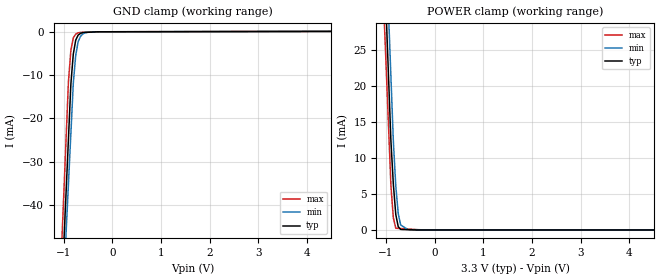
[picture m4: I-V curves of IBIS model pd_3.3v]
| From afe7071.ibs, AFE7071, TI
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[Model] pd_3.3v
Model_type Input
Vinl = 1.00000V
Vinh = 2.30000V
C_comp 542.000fF 490.000fF 594.000fF
| variable typ   min   max
[Voltage Range] 3.30000V 3.00000V 3.60000V
[POWER Clamp Reference] 3.30000V 3.00000V 3.60000V
[GND Clamp Reference] 0.00000V 0.00000V 0.00000V
[Temperature Range] 25   85   -40
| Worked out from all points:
|   GND clamp passes 1 mA (typ) near -0.71 V on its own axis
|   POWER clamp passes 1 mA (typ) near -0.77 V on its own axis
[GND Clamp]
-3.3V     -635.6mA   -594.3mA   -666.4mA
-900mV    -24.85mA   -35.21mA   -11.56mA
-850mV    -12.12mA   -23.56mA   -4.343mA
-800mV    -5.166mA   -11.91mA   -1.421mA
-750mV    -1.931mA   -5.437mA   -532.7uA
-700mV    -771.9uA   -2.269mA   -250.8uA
-650mV    -374.6uA   -1.047mA   -145.5uA
-600mV    -184.5uA   -476.1uA   -124.7uA
-500mV    -126.6uA   -113.9uA   -83.27uA
-250mV    -9.811uA   -10.13uA   -8.878uA
6.6V      109.1uA    119.5uA    156.9uA
[POWER Clamp]
-3.3V     450mA      451.7mA    409.4mA
-1.1V     48.81mA    57.14mA    39.75mA
-900mV    12.34mA    21.28mA    6.151mA
-850mV    6.331mA    12.31mA    1.665mA
-800mV    2.138mA    6.102mA    241.1uA
-750mV    463.4uA    2.283mA    219.2uA
-700mV    77.46uA    687.5uA    197.3uA
-550mV    44.26uA    61.72uA    131.5uA
-175mV    0A         0A         0A
6.6V      0A         0A         0A
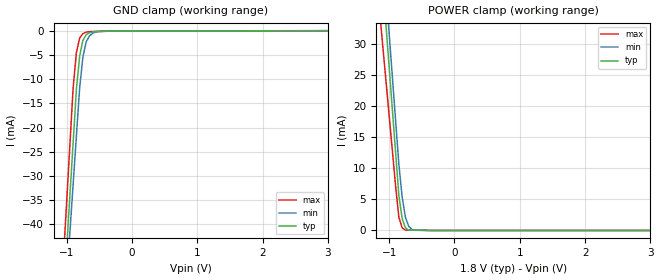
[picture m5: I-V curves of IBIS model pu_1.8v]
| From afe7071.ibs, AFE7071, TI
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[Model] pu_1.8v
Model_type Input
Vinl = 540.000mV
Vinh = 1.25000V
C_comp 562.000fF 550.000fF 574.000fF
| variable typ   min   max
[Voltage Range] 1.80000V 1.71000V 1.89000V
[POWER Clamp Reference] 1.80000V 1.71000V 1.89000V
[GND Clamp Reference] 0.00000V 0.00000V 0.00000V
[Temperature Range] 25   85   -40
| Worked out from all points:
|   GND clamp passes 1 mA (typ) near -0.71 V on its own axis
|   POWER clamp passes 1 mA (typ) near -0.77 V on its own axis
[GND Clamp]
-1.8V     -221.6mA   -211.4mA   -225.6mA
-900mV    -23.14mA   -31.74mA   -11.79mA
-850mV    -12.12mA   -21.76mA   -4.497mA
-800mV    -5.194mA   -11.78mA   -1.488mA
-750mV    -1.953mA   -5.371mA   -562.4uA
-700mV    -788.3uA   -2.247mA   -269.4uA
-650mV    -388.9uA   -1.041mA   -161.7uA
-600mV    -199.3uA   -481.2uA   -144.1uA
-500mV    -97.97uA   -129.3uA   -109uA
3.6V      49.78uA    63.83uA    37uA
[POWER Clamp]
-1.8V     137.2mA    144.9mA    110.2mA
-950mV    19.41mA    24.7mA     12.82mA
-900mV    12.47mA    17.63mA    7.092mA
-850mV    5.544mA    10.56mA    2.105mA
-800mV    1.926mA    5.358mA    405.2uA
-750mV    411.9uA    2.124mA    58.62uA
-700mV    59.34uA    668.9uA    51.56uA
-650mV    50.87uA    151.1uA    44.49uA
-600mV    42.39uA    65.71uA    37.43uA
3.6V      0A         0A         0A
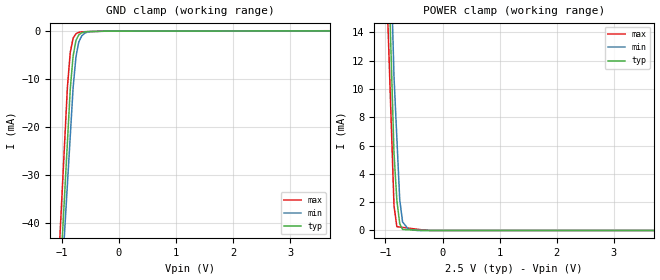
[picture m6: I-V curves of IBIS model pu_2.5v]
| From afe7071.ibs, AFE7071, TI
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[Model] pu_2.5v
Model_type Input
Vinl = 750.000mV
Vinh = 1.75000V
C_comp 562.000fF 550.000fF 574.000fF
| variable typ   min   max
[Voltage Range] 2.50000V 2.25000V 2.75000V
[POWER Clamp Reference] 2.50000V 2.25000V 2.75000V
[GND Clamp Reference] 0.00000V 0.00000V 0.00000V
[Temperature Range] 25   85   -40
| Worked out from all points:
|   GND clamp passes 1 mA (typ) near -0.71 V on its own axis
|   POWER clamp passes 1 mA (typ) near -0.77 V on its own axis
[GND Clamp]
-2.5V     -380mA     -355.4mA   -392.3mA
-900mV    -23.29mA   -32.02mA   -11.72mA
-850mV    -12.14mA   -21.91mA   -4.466mA
-800mV    -5.212mA   -11.81mA   -1.478mA
-750mV    -1.963mA   -5.391mA   -563uA
-700mV    -794.6uA   -2.258mA   -273.3uA
-650mV    -395uA     -1.05mA    -167.3uA
-600mV    -205.4uA   -487uA     -149.7uA
-500mV    -106.1uA   -135.2uA   -114.4uA
5V        64.59uA    60.83uA    92.3uA
[POWER Clamp]
-2.5V     230.4mA    251.3mA    219.8mA
-1.05V    32.71mA    40.01mA    25.86mA
-850mV    5.448mA    10.86mA    1.747mA
-800mV    2.13mA     6.526mA    267.4uA
-750mV    483.8uA    2.192mA    241.9uA
-700mV    70.55uA    605.6uA    216.5uA
-600mV    50.4uA     94.11uA    165.5uA
-450mV    20.16uA    0A         89.13uA
-200mV    0A         0A         0A
5V        0A         0A         0A
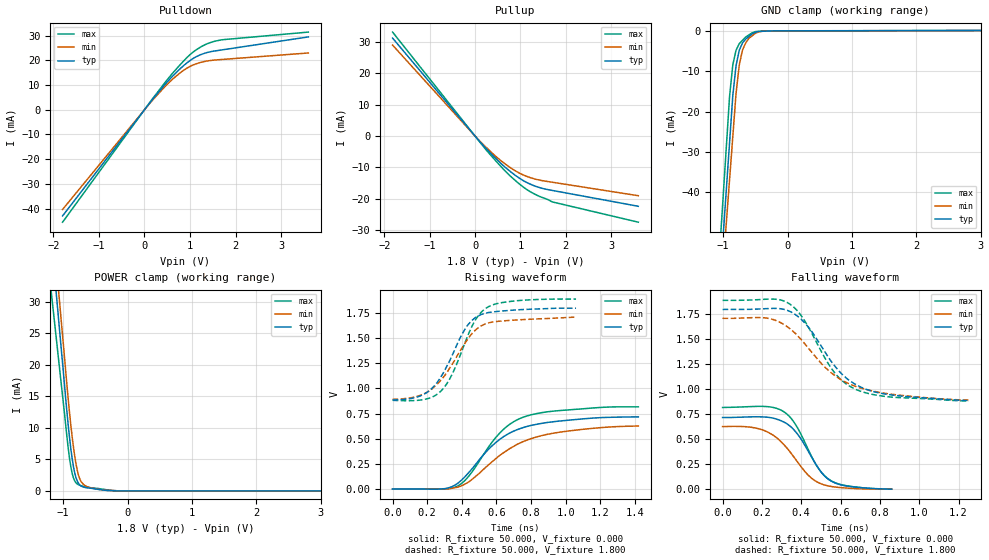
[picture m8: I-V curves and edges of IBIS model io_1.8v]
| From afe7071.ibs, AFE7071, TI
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[Model]   io_1.8v
Model_type I/O
Vinl=5.400E-01
Vinh=1.250E+00
Vref=0.000E+00
Rref=1.000E+06
Cref=1.500E-12
Vmeas=9.000E-01
C_comp   4.360E-13   4.000E-13   4.720E-13
[Voltage Range]   1.800E+00   1.710E+00   1.890E+00
[POWER Clamp Reference]   1.800E+00   1.710E+00   1.890E+00
[GND Clamp Reference]   0.000E+00   0.000E+00   0.000E+00
[Pullup Reference]   1.800E+00   1.710E+00   1.890E+00
[Pulldown Reference]   0.000E+00   0.000E+00   0.000E+00
[Temperature Range]   25   85   -40
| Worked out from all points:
|   slope of the pulldown table from 0 to 0.27 V, typ, clamps not added: 43.4 ohm
|   slope of the pullup table from 0 to 0.27 V, typ, clamps not added: 62 ohm
|   GND clamp passes 1 mA (typ) near -0.57 V on its own axis
|   POWER clamp passes 1 mA (typ) near -0.75 V on its own axis
|   rising waveform, R_fixture 50.000, V_fixture 0.000: 20-80 % time 268ps typ, 320ps min, 229ps max; typ from 0 V to 0.717 V
|   falling waveform, R_fixture 50.000, V_fixture 0.000: 20-80 % time 142ps typ, 161ps min, 136ps max; typ from 0.717 V to 0 V
|   rising waveform, R_fixture 50.000, V_fixture 1.800: 20-80 % time 167ps typ, 193ps min, 155ps max; typ from 0.886 V to 1.8 V
|   falling waveform, R_fixture 50.000, V_fixture 1.800: 20-80 % time 221ps typ, 266ps min, 193ps max; typ from 1.8 V to 0.886 V
[GND Clamp]
-1.8V     -236.1mA   -227.9mA   -240.1mA
-900mV    -27.61mA   -36.78mA   -16.16mA
-850mV    -16.02mA   -26.16mA   -8.42mA
-800mV    -8.649mA   -15.55mA   -4.816mA
-750mV    -4.824mA   -8.529mA   -3.182mA
-700mV    -3.016mA   -4.771mA   -2.357mA
-650mV    -2.052mA   -2.994mA   -1.533mA
-600mV    -1.403mA   -1.853mA   -1.009mA
-550mV    -754.4uA   -1.234mA   -485.4uA
-400mV    -116.2uA   -108.8uA   -124uA
-200mV    -9.259uA   -11.12uA   -12.43uA
3.6V      125.7uA    67.76uA    71.02uA
[Power Clamp]
-1.82V    111.8mA    116.9mA    89.74mA
-1.76V    105.1mA    110.7mA    85.43mA
-1.02V    21.47mA    25.85mA    16.06mA
-940mV    12.37mA    16.61mA    8.48mA
-880mV    6.628mA    10.36mA    3.792mA
-860mV    5.121mA    8.572mA    2.78mA
-820mV    2.838mA    5.499mA    1.581mA
-760mV    1.173mA    2.452mA    972.7uA
-720mV    768.7uA    1.456mA    825.9uA
-640mV    507.6uA    722.6uA    627.6uA
-320mV    72.94uA    86.73uA    178.8uA
3.6V      0A         0A         0A
[Pullup]
-1.82V    31.26mA    29.03mA    33.17mA
140mV     -2.332mA   -2.134mA   -2.556mA
580mV     -8.865mA   -7.98mA    -9.867mA
800mV     -11.56mA   -10.29mA   -13.05mA
1.06V     -14.17mA   -12.38mA   -16.21mA
1.34V     -16.04mA   -13.77mA   -18.7mA
1.7V      -17.32mA   -14.71mA   -20.98mA
3.6V      -22.38mA   -19.01mA   -27.46mA
[Pulldown]
-1.8V     -42.97mA   -40.36mA   -45.52mA
0V        0A         0A         0A
380mV     8.668mA    7.991mA    9.317mA
600mV     13.28mA    12.1mA     14.42mA
800mV     16.88mA    15.16mA    18.55mA
1.08V     20.87mA    18.2mA     23.5mA
1.22V     22.19mA    19.08mA    25.23mA
1.38V     23.18mA    19.73mA    26.73mA
1.7V      24.21mA    20.34mA    28.32mA
3.6V      29.47mA    22.97mA    31.42mA
[Rising Waveform]
R_fixture = 50.000
V_fixture = 0.000
V_fixture_min = 0.000
V_fixture_max = 0.000
|  time   V(typ)   V(min)   V(max)
0s        49.28uV    165.4uV    177.3uV
300ps     3.366mV    757.9uV    -189.1uV
380ps     60.88mV    20.15mV    33.2mV
440ps     163.2mV    70.27mV    126.8mV
540ps     368.8mV    218.2mV    381.2mV
620ps     494.6mV    335.4mV    557.8mV
680ps     559.5mV    404.8mV    647.4mV
760ps     613.8mV    475.9mV    717.2mV
1ns       681.5mV    573.4mV    784.7mV
1.42ns    716.9mV    625.9mV    817.1mV
[Falling Waveform]
R_fixture = 50.000
V_fixture = 0.000
V_fixture_min = 0.000
V_fixture_max = 0.000
|  time   V(typ)   V(min)   V(max)
0s        716.9mV    625.9mV    817.1mV
180ps     724.2mV    606.2mV    828.4mV
250ps     713.6mV    548.8mV    820.3mV
300ps     682.5mV    469.4mV    788.1mV
370ps     578mV      302.7mV    650.3mV
440ps     365.2mV    132.2mV    378.5mV
490ps     202.2mV    63.49mV    201.1mV
540ps     96.91mV    31.63mV    99.19mV
630ps     31.98mV    11.26mV    34.44mV
860ps     49.28uV    165.4uV    177.3uV
[Rising Waveform]
R_fixture = 50.000
V_fixture = 1.800
V_fixture_min = 1.710
V_fixture_max = 1.890
|  time   V(typ)   V(min)   V(max)
0s        886.1mV    892.4mV    882.2mV
170ps     933.4mV    938.6mV    886.9mV
220ps     989.1mV    985.4mV    908.5mV
280ps     1.117V     1.084V     975.2mV
340ps     1.312V     1.228V     1.128V
420ps     1.595V     1.453V     1.461V
490ps     1.717V     1.597V     1.711V
550ps     1.754V     1.65V      1.809V
620ps     1.768V     1.669V     1.85V
1.06ns    1.798V     1.709V     1.889V
[Falling Waveform]
R_fixture = 50.000
V_fixture = 1.800
V_fixture_min = 1.710
V_fixture_max = 1.890
|  time   V(typ)   V(min)   V(max)
0s        1.798V     1.709V     1.889V
220ps     1.806V     1.713V     1.9V
340ps     1.781V     1.609V     1.855V
390ps     1.717V     1.517V     1.762V
430ps     1.636V     1.426V     1.644V
570ps     1.234V     1.139V     1.165V
620ps     1.128V     1.077V     1.066V
680ps     1.044V     1.026V     996.6mV
850ps     945mV      952.3mV    923.2mV
1.25ns    886.1mV    892.4mV    882.2mV
[Ramp]
dV/dt_r   4.2300E-01/2.6740E-10   3.6800E-01/3.1990E-10   4.8100E-01/1.4870E-10
dV/dt_f   5.4800E-01/2.2130E-10   4.9100E-01/2.6560E-10   6.0400E-01/1.9290E-10
R_load = 50
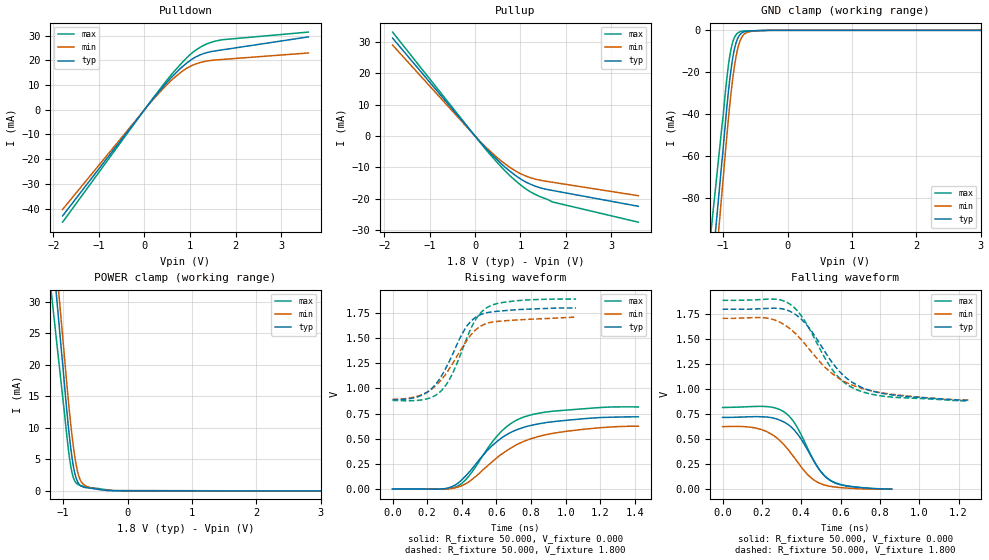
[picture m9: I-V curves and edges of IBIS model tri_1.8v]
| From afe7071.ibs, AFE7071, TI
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[Model]   tri_1.8v
Model_type 3-state
Vref=0.000E+00
Rref=1.000E+06
Cref=1.500E-12
Vmeas=9.000E-01
C_comp   4.840E-13   4.750E-13   4.930E-13
[Voltage Range]   1.800E+00   1.710E+00   1.890E+00
[POWER Clamp Reference]   1.800E+00   1.710E+00   1.890E+00
[GND Clamp Reference]   0.000E+00   0.000E+00   0.000E+00
[Pullup Reference]   1.800E+00   1.710E+00   1.890E+00
[Pulldown Reference]   0.000E+00   0.000E+00   0.000E+00
[Temperature Range]   25   85   -40
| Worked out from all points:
|   slope of the pulldown table from 0 to 0.27 V, typ, clamps not added: 43.4 ohm
|   slope of the pullup table from 0 to 0.27 V, typ, clamps not added: 62 ohm
|   GND clamp passes 1 mA (typ) near -0.70 V on its own axis
|   POWER clamp passes 1 mA (typ) near -0.75 V on its own axis
|   rising waveform, R_fixture 50.000, V_fixture 0.000: 20-80 % time 268ps typ, 320ps min, 229ps max; typ from 0 V to 0.717 V
|   falling waveform, R_fixture 50.000, V_fixture 0.000: 20-80 % time 142ps typ, 161ps min, 136ps max; typ from 0.717 V to 0 V
|   rising waveform, R_fixture 50.000, V_fixture 1.800: 20-80 % time 167ps typ, 194ps min, 155ps max; typ from 0.887 V to 1.8 V
|   falling waveform, R_fixture 50.000, V_fixture 1.800: 20-80 % time 221ps typ, 266ps min, 193ps max; typ from 1.8 V to 0.887 V
[GND Clamp]
-1.8V     -323.2mA   -353.4mA   -275.9mA
-1.02V    -62.73mA   -77.74mA   -45.99mA
-940mV    -35.81mA   -49.33mA   -22.1mA
-900mV    -24.11mA   -36.38mA   -12.79mA
-880mV    -19.15mA   -30.55mA   -9.297mA
-840mV    -11.2mA    -20.4mA    -4.552mA
-820mV    -8.255mA   -16.17mA   -3.113mA
-760mV    -2.989mA   -7.13mA    -981.1uA
-720mV    -1.466mA   -3.788mA   -499.9uA
-660mV    -617.7uA   -1.499mA   -294.2uA
-460mV    -147.3uA   -189.5uA   -131.9uA
3.6V      0A         0A         0A
[Power Clamp]
-1.8V     109.6mA    115.7mA    89.51mA
-1.76V    105.1mA    110.7mA    85.43mA
-1.02V    21.47mA    25.85mA    16.06mA
-940mV    12.37mA    16.61mA    8.48mA
-880mV    6.628mA    10.36mA    3.792mA
-860mV    5.121mA    8.572mA    2.78mA
-820mV    2.838mA    5.499mA    1.581mA
-760mV    1.173mA    2.452mA    972.7uA
-720mV    768.7uA    1.456mA    825.9uA
-640mV    507.6uA    722.6uA    627.6uA
-320mV    72.94uA    86.73uA    178.8uA
3.6V      0A         0A         0A
[Pullup]
-1.82V    31.26mA    29.03mA    33.17mA
140mV     -2.332mA   -2.134mA   -2.556mA
580mV     -8.865mA   -7.98mA    -9.867mA
800mV     -11.56mA   -10.29mA   -13.05mA
1.06V     -14.17mA   -12.38mA   -16.21mA
1.34V     -16.04mA   -13.77mA   -18.7mA
1.7V      -17.32mA   -14.71mA   -20.98mA
3.6V      -22.38mA   -19.01mA   -27.46mA
[Pulldown]
-1.8V     -42.97mA   -40.36mA   -45.52mA
0V        0A         0A         0A
380mV     8.668mA    7.991mA    9.317mA
600mV     13.28mA    12.1mA     14.42mA
800mV     16.88mA    15.16mA    18.55mA
1.08V     20.87mA    18.2mA     23.5mA
1.22V     22.19mA    19.08mA    25.23mA
1.38V     23.18mA    19.73mA    26.73mA
1.7V      24.21mA    20.34mA    28.32mA
3.6V      29.47mA    22.97mA    31.42mA
[Rising Waveform]
R_fixture = 50.000
V_fixture = 0.000
V_fixture_min = 0.000
V_fixture_max = 0.000
|  time   V(typ)   V(min)   V(max)
0s        -144.8uV   -503.5uV   -468uV
300ps     3.175mV    88.81uV    -834.4uV
380ps     60.75mV    19.47mV    32.55mV
440ps     163.1mV    69.57mV    126.2mV
540ps     369mV      217.4mV    380.6mV
620ps     494.9mV    334.6mV    557.2mV
680ps     559.9mV    404mV      646.7mV
760ps     614.2mV    475.1mV    716.5mV
1ns       682mV      572.6mV    784mV
1.42ns    717.5mV    625mV      816.4mV
[Falling Waveform]
R_fixture = 50.000
V_fixture = 0.000
V_fixture_min = 0.000
V_fixture_max = 0.000
|  time   V(typ)   V(min)   V(max)
0s        717.5mV    625mV      816.4mV
180ps     724.7mV    605.3mV    827.7mV
250ps     714.2mV    547.9mV    819.6mV
300ps     683mV      468.5mV    787.4mV
370ps     578.3mV    302mV      649.7mV
440ps     365.3mV    131.5mV    377.8mV
490ps     202.2mV    62.8mV     200.4mV
540ps     96.81mV    30.95mV    98.54mV
630ps     31.82mV    10.58mV    33.79mV
860ps     -144.8uV   -503.5uV   -468uV
[Rising Waveform]
R_fixture = 50.000
V_fixture = 1.800
V_fixture_min = 1.710
V_fixture_max = 1.890
|  time   V(typ)   V(min)   V(max)
0s        886.7mV    891.8mV    881.6mV
170ps     934mV      938.3mV    886.4mV
220ps     989.7mV    984.9mV    908mV
280ps     1.118V     1.084V     974.8mV
340ps     1.313V     1.227V     1.127V
420ps     1.596V     1.453V     1.461V
490ps     1.718V     1.596V     1.711V
540ps     1.752V     1.644V     1.798V
620ps     1.77V      1.669V     1.85V
1.06ns    1.8V       1.709V     1.889V
[Falling Waveform]
R_fixture = 50.000
V_fixture = 1.800
V_fixture_min = 1.710
V_fixture_max = 1.890
|  time   V(typ)   V(min)   V(max)
0s        1.8V       1.709V     1.889V
220ps     1.808V     1.713V     1.9V
340ps     1.782V     1.608V     1.854V
390ps     1.718V     1.517V     1.762V
430ps     1.638V     1.425V     1.643V
570ps     1.235V     1.138V     1.165V
620ps     1.129V     1.076V     1.066V
680ps     1.045V     1.025V     996.1mV
850ps     945.7mV    951.7mV    922.7mV
1.25ns    886.7mV    891.8mV    881.6mV
[Ramp]
dV/dt_r   4.2300E-01/2.6740E-10   3.6800E-01/3.1990E-10   4.8100E-01/1.4870E-10
dV/dt_f   5.4800E-01/2.2130E-10   4.9100E-01/2.6560E-10   6.0400E-01/1.9290E-10
R_load = 50
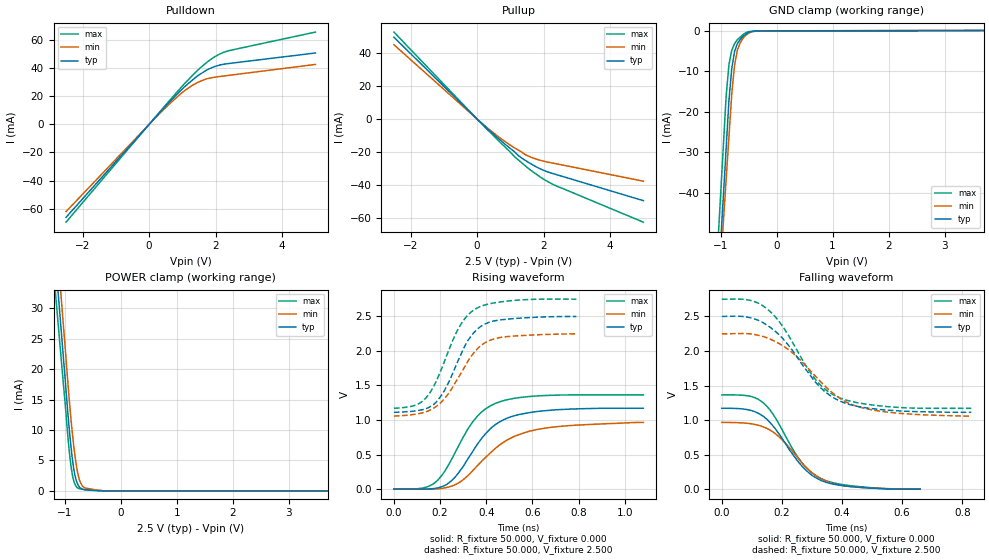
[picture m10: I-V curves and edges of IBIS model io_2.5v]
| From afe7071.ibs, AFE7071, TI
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[Model]   io_2.5v
Model_type I/O
Vinl=7.500E-01
Vinh=1.750E+00
Vref=0.000E+00
Rref=1.000E+06
Cref=0.000E+00
Vmeas=1.250E+00
C_comp   4.360E-13   4.000E-13   4.720E-13
[Voltage Range]   2.500E+00   2.250E+00   2.750E+00
[POWER Clamp Reference]   2.500E+00   2.250E+00   2.750E+00
[GND Clamp Reference]   0.000E+00   0.000E+00   0.000E+00
[Pullup Reference]   2.500E+00   2.250E+00   2.750E+00
[Pulldown Reference]   0.000E+00   0.000E+00   0.000E+00
[Temperature Range]   25   85   -40
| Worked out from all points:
|   slope of the pulldown table from 0 to 0.375 V, typ, clamps not added: 38.2 ohm
|   slope of the pullup table from 0 to 0.375 V, typ, clamps not added: 53.3 ohm
|   GND clamp passes 1 mA (typ) near -0.56 V on its own axis
|   POWER clamp passes 1 mA (typ) near -0.76 V on its own axis
|   rising waveform, R_fixture 50.000, V_fixture 0.000: 20-80 % time 161ps typ, 208ps min, 149ps max; typ from 0 V to 1.17 V
|   falling waveform, R_fixture 50.000, V_fixture 0.000: 20-80 % time 124ps typ, 128ps min, 120ps max; typ from 1.17 V to 0 V
|   rising waveform, R_fixture 50.000, V_fixture 2.500: 20-80 % time 124ps typ, 141ps min, 128ps max; typ from 1.11 V to 2.5 V
|   falling waveform, R_fixture 50.000, V_fixture 2.500: 20-80 % time 156ps typ, 175ps min, 144ps max; typ from 2.5 V to 1.11 V
[GND Clamp]
-2.5V     -408.8mA   -375.1mA   -412mA
-900mV    -29mA      -36.72mA   -16.07mA
-850mV    -17.13mA   -26.15mA   -8.365mA
-800mV    -9.303mA   -15.57mA   -4.792mA
-750mV    -5.128mA   -8.543mA   -3.172mA
-700mV    -3.157mA   -4.777mA   -2.199mA
-650mV    -2.135mA   -2.997mA   -1.566mA
-600mV    -1.36mA    -1.854mA   -932uA
-550mV    -879.6uA   -1.114mA   -482.3uA
-450mV    -160uA     -289.1uA   -159.8uA
-350mV    -39.55uA   -35.59uA   -86.93uA
5V        96.37uA    125.8uA    86.21uA
[Power Clamp]
-2.5V     189.6mA    199.8mA    174mA
-2.46V    185.1mA    194.8mA    169.4mA
-1.02V    21.48mA    26.74mA    17.15mA
-940mV    12.32mA    17.33mA    8.54mA
-900mV    8.299mA    12.97mA    4.932mA
-880mV    6.546mA    10.97mA    3.553mA
-820mV    2.682mA    5.936mA    1.139mA
-760mV    955.2uA    2.587mA    449uA
-720mV    477.6uA    1.366mA    324.7uA
-640mV    191.6uA    479.4uA    215.5uA
-280mV    0A         0A         0A
5V        0A         0A         0A
[Pullup]
-2.5V     49.56mA    45.02mA    52.66mA
260mV     -4.9mA     -4.526mA   -5.459mA
840mV     -15.25mA   -13.62mA   -16.91mA
1.1V      -19.42mA   -17.16mA   -22.29mA
1.24V     -22.15mA   -18.82mA   -24.74mA
1.44V     -24.92mA   -21.47mA   -28.19mA
1.86V     -29.8mA    -24.77mA   -34.57mA
2.28V     -33.05mA   -26.71mA   -39.58mA
5V        -49.44mA   -37.66mA   -62.5mA
[Pulldown]
-2.5V     -66.25mA   -62.13mA   -69.66mA
140mV     3.741mA    3.488mA    3.947mA
600mV     15.6mA     14.35mA    16.63mA
1V        25.3mA     22.79mA    27.35mA
1.26V     30.77mA    27.2mA     33.84mA
1.46V     34.63mA    29.86mA    38.55mA
1.68V     37.97mA    32.03mA    43.1mA
1.94V     40.92mA    33.5mA     47.67mA
2.28V     42.99mA    34.57mA    51.66mA
5V        50.86mA    42.71mA    65.74mA
[Rising Waveform]
R_fixture = 50.000
V_fixture = 0.000
V_fixture_min = 0.000
V_fixture_max = 0.000
|  time   V(typ)   V(min)   V(max)
0s        48.34uV    11.82uV    193.3uV
150ps     1.657mV    -245uV     40.28mV
190ps     18.38mV    4.771mV    131.6mV
230ps     71.7mV     24.96mV    313.2mV
280ps     236.8mV    90.2mV     626.6mV
340ps     539.1mV    263.2mV    968.8mV
440ps     936.1mV    592.2mV    1.242V
520ps     1.061V     761.5mV    1.314V
640ps     1.131V     875.2mV    1.353V
1.08ns    1.171V     965.9mV    1.364V
[Falling Waveform]
R_fixture = 50.000
V_fixture = 0.000
V_fixture_min = 0.000
V_fixture_max = 0.000
|  time   V(typ)   V(min)   V(max)
0s        1.171V     965.9mV    1.364V
90ps      1.147V     950.9mV    1.349V
140ps     1.048V     898mV      1.242V
160ps     967.1mV    856.1mV    1.148V
190ps     801.1mV    759.2mV    944mV
260ps     366.6mV    414.6mV    419.3mV
290ps     234.8mV    275.3mV    272mV
330ps     126.9mV    151.6mV    153.6mV
420ps     41.88mV    41.81mV    54.83mV
660ps     48.34uV    11.82uV    193.3uV
[Rising Waveform]
R_fixture = 50.000
V_fixture = 2.500
V_fixture_min = 2.250
V_fixture_max = 2.750
|  time   V(typ)   V(min)   V(max)
0s        1.113V     1.058V     1.17V
110ps     1.141V     1.094V     1.241V
150ps     1.181V     1.134V     1.367V
180ps     1.249V     1.189V     1.539V
220ps     1.435V     1.316V     1.859V
280ps     1.874V     1.619V     2.328V
350ps     2.278V     1.988V     2.602V
400ps     2.399V     2.129V     2.671V
460ps     2.449V     2.195V     2.709V
790ps     2.499V     2.248V     2.749V
[Falling Waveform]
R_fixture = 50.000
V_fixture = 2.500
V_fixture_min = 2.250
V_fixture_max = 2.750
|  time   V(typ)   V(min)   V(max)
0s        2.499V     2.248V     2.749V
90ps      2.486V     2.25V      2.737V
150ps     2.375V     2.191V     2.611V
200ps     2.193V     2.083V     2.372V
310ps     1.556V     1.642V     1.596V
350ps     1.389V     1.463V     1.425V
390ps     1.281V     1.323V     1.327V
450ps     1.199V     1.2V       1.252V
530ps     1.152V     1.126V     1.204V
830ps     1.113V     1.058V     1.17V
[Ramp]
dV/dt_r   6.9200E-01/1.6090E-10   5.6700E-01/2.0820E-10   8.0400E-01/1.4870E-10
dV/dt_f   8.3100E-01/1.5640E-10   7.1500E-01/1.7540E-10   9.4865E-01/1.4369E-10
R_load = 50
